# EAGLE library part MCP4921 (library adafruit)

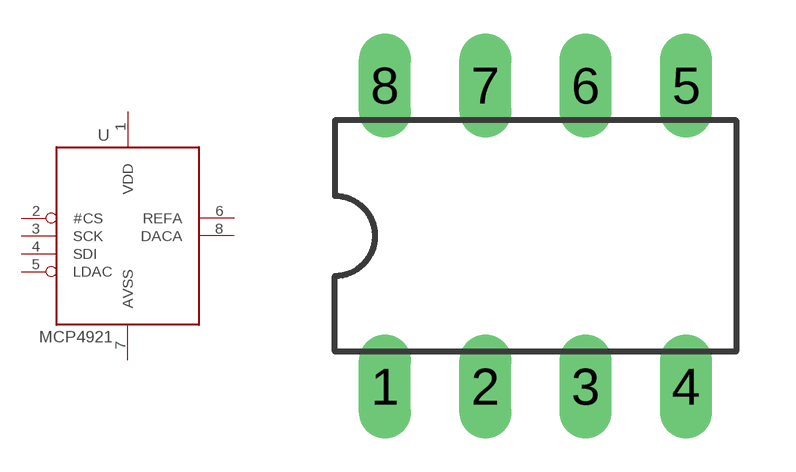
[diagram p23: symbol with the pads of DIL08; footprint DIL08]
Designator prefix -

## MCP4921  [DIL08]
1  VDD  sup
2  #CS  in
3  SCK  in
4  SDI  in
5  LDAC  in
6  REFA  in
7  AVSS  sup
8  DACA  out

## Footprint DIL08 (pad centres in mm)
Dual In Line Package
drill 0.813 long: 1 -3.81,-3.81; 2 -1.27,-3.81; 3 1.27,-3.81; 4 3.81,-3.81; 5 3.81,3.81; 6 1.27,3.81; 7 -1.27,3.81; 8 -3.81,3.81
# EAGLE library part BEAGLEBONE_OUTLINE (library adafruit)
Should match A3 pinout - but not completely tested

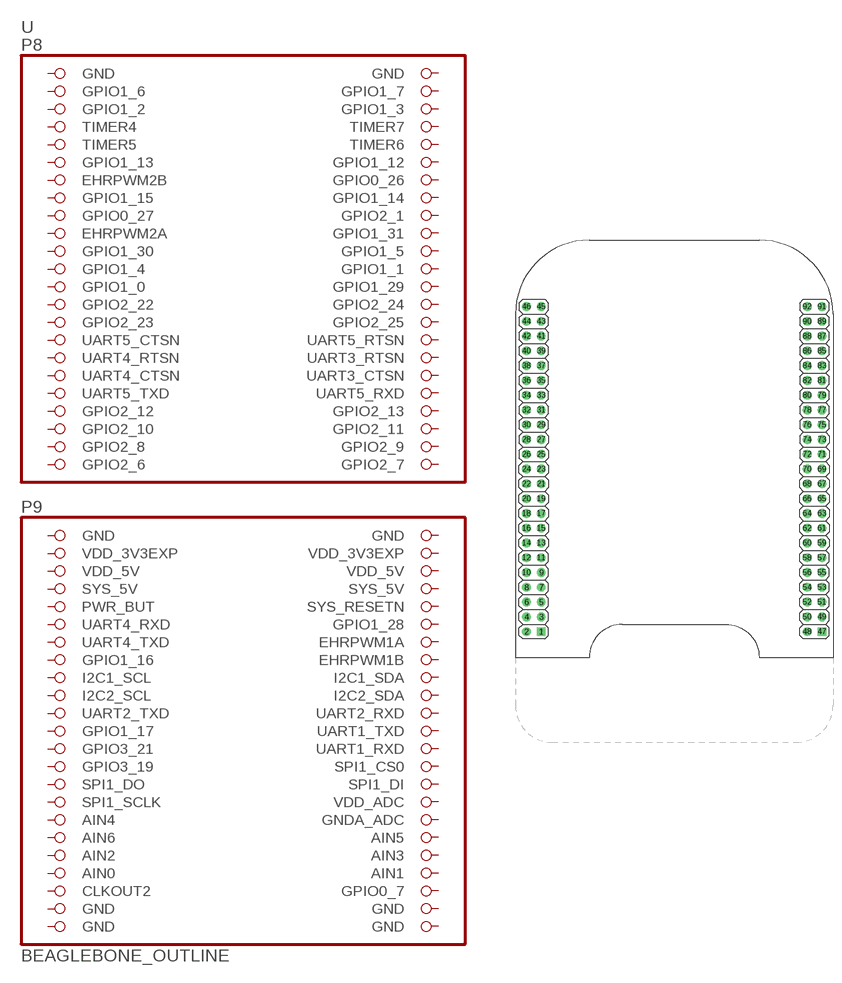
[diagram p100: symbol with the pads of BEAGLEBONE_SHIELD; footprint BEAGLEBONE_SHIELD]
Designator prefix -

## BEAGLEBONE_OUTLINE  [BEAGLEBONE_SHIELD]
1  GND  pwr
2  GND  pwr
3  GPIO1_6  pas
4  GPIO1_7  pas
5  GPIO1_2  pas
6  GPIO1_3  pas
7  TIMER4  pas
8  TIMER7  pas
9  TIMER5  pas
10  TIMER6  pas
11  GPIO1_13  pas
12  GPIO1_12  pas
13  EHRPWM2B  pas
14  GPIO0_26  pas
15  GPIO1_15  pas
16  GPIO1_14  pas
17  GPIO0_27  pas
18  GPIO2_1  pas
19  EHRPWM2A  pas
20  GPIO1_31  pas
21  GPIO1_30  pas
22  GPIO1_5  pas
23  GPIO1_4  pas
24  GPIO1_1  pas
25  GPIO1_0  pas
26  GPIO1_29  pas
27  GPIO2_22  pas
28  GPIO2_24  pas
29  GPIO2_23  pas
30  GPIO2_25  pas
31  UART5_CTSN  pas
32  UART5_RTSN  pas
33  UART4_RTSN  pas
34  UART3_RTSN  pas
35  UART4_CTSN  pas
36  UART3_CTSN  pas
37  UART5_TXD  pas
38  UART5_RXD  pas
39  GPIO2_12  pas
40  GPIO2_13  pas
41  GPIO2_10  pas
42  GPIO2_11  pas
43  GPIO2_8  pas
44  GPIO2_9  pas
45  GPIO2_6  pas
46  GPIO2_7  pas
47  GND  pwr
48  GND  pwr
49  VDD_3V3EXP  pwr
50  VDD_3V3EXP  pwr
51  VDD_5V  pwr
52  VDD_5V  pwr
53  SYS_5V  pwr
54  SYS_5V  pas
55  PWR_BUT  pas
56  SYS_RESETN  pas
57  UART4_RXD  pas
58  GPIO1_28  pas
59  UART4_TXD  pas
60  EHRPWM1A  pas
61  GPIO1_16  pas
62  EHRPWM1B  pas
63  I2C1_SCL  pas
64  I2C1_SDA  pas
65  I2C2_SCL  pas
66  I2C2_SDA  pas
67  UART2_TXD  pas
68  UART2_RXD  pas
69  GPIO1_17  pas
70  UART1_TXD  pas
71  GPIO3_21  pas
72  UART1_RXD  pas
73  GPIO3_19  pas
74  SPI1_CS0  pas
75  SPI1_DO  pas
76  SPI1_DI  pas
77  SPI1_SCLK  pas
78  VDD_ADC  pas
79  AIN4  pas
80  GNDA_ADC  pas
81  AIN6  pas
82  AIN5  pas
83  AIN2  pas
84  AIN3  pas
85  AIN0  pwr
86  AIN1  pas
87  CLKOUT2  in
88  GPIO0_7  pas
89  GND  pwr
90  GND  pwr
91  GND  pwr
92  GND  pwr

## Footprint BEAGLEBONE_SHIELD (pad centres in mm)
drill 1 square: 1 4.445,19.05; 47 52.705,19.05
drill 1: 2 1.905,19.05; 3 4.445,21.59; 4 1.905,21.59; 5 4.445,24.13; 6 1.905,24.13; 7 4.445,26.67; 8 1.905,26.67; 9 4.445,29.21; 10 1.905,29.21; 11 4.445,31.75; 12 1.905,31.75; 13 4.445,34.29; 14 1.905,34.29; 15 4.445,36.83; 16 1.905,36.83; 17 4.445,39.37; 18 1.905,39.37; 19 4.445,41.91; 20 1.905,41.91; 21 4.445,44.45; 22 1.905,44.45; 23 4.445,46.99; 24 1.905,46.99; 25 4.445,49.53; 26 1.905,49.53; 27 4.445,52.07; 28 1.905,52.07; 29 4.445,54.61; 30 1.905,54.61; 31 4.445,57.15; 32 1.905,57.15; 33 4.445,59.69; 34 1.905,59.69; 35 4.445,62.23; 36 1.905,62.23; 37 4.445,64.77; 38 1.905,64.77; 39 4.445,67.31; 40 1.905,67.31; 41 4.445,69.85; 42 1.905,69.85; 43 4.445,72.39; 44 1.905,72.39; 45 4.445,74.93; 46 1.905,74.93; 48 50.165,19.05; 49 52.705,21.59; 50 50.165,21.59; 51 52.705,24.13; 52 50.165,24.13; 53 52.705,26.67; 54 50.165,26.67; 55 52.705,29.21; 56 50.165,29.21; 57 52.705,31.75; 58 50.165,31.75; 59 52.705,34.29; 60 50.165,34.29; 61 52.705,36.83; 62 50.165,36.83; 63 52.705,39.37; 64 50.165,39.37; 65 52.705,41.91; 66 50.165,41.91; 67 52.705,44.45; 68 50.165,44.45; 69 52.705,46.99; 70 50.165,46.99; 71 52.705,49.53; 72 50.165,49.53; 73 52.705,52.07; 74 50.165,52.07; 75 52.705,54.61; 76 50.165,54.61; 77 52.705,57.15; 78 50.165,57.15; 79 52.705,59.69; 80 50.165,59.69; 81 52.705,62.23; 82 50.165,62.23; 83 52.705,64.77; 84 50.165,64.77; 85 52.705,67.31; 86 50.165,67.31; 87 52.705,69.85; 88 50.165,69.85; 89 52.705,72.39; 90 50.165,72.39; 91 52.705,74.93; 92 50.165,74.93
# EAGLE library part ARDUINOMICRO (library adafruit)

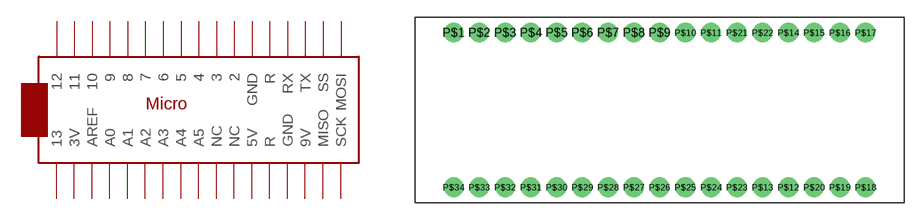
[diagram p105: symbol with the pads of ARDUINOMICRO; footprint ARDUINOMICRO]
Designator prefix -

## ARDUINOMICRO  [ARDUINOMICRO]
P$1  12
P$2  11
P$3  10
P$4  9
P$5  8
P$6  7
P$7  6
P$8  5
P$9  4
P$10  3
P$11  2
P$12  GND
P$13  R
P$14  RX
P$15  TX
P$16  SS
P$17  MOSI
P$18  SCK
P$19  MISO
P$20  9V
P$21  GND
P$22  R
P$23  5V
P$24  NC
P$25  NC
P$26  A5
P$27  A4
P$28  A3
P$29  A2
P$30  A1
P$31  A0
P$32  AREF
P$33  3V
P$34  13

## Footprint ARDUINOMICRO (pad centres in mm)
drill 1.1 pad 1.93: P$1 -20.32,7.62; P$2 -17.78,7.62; P$3 -15.24,7.62; P$4 -12.7,7.62; P$5 -10.16,7.62; P$6 -7.62,7.62; P$7 -5.08,7.62; P$8 -2.54,7.62; P$9 0,7.62; P$10 2.54,7.62; P$11 5.08,7.62; P$12 12.7,-7.62; P$13 10.16,-7.62; P$14 12.7,7.62; P$15 15.24,7.62; P$16 17.78,7.62; P$17 20.32,7.62; P$18 20.32,-7.62; P$19 17.78,-7.62; P$20 15.24,-7.62; P$21 7.62,7.62; P$22 10.16,7.62; P$23 7.62,-7.62; P$24 5.08,-7.62; P$25 2.54,-7.62; P$26 0,-7.62; P$27 -2.54,-7.62; P$28 -5.08,-7.62; P$29 -7.62,-7.62; P$30 -10.16,-7.62; P$31 -12.7,-7.62; P$32 -15.24,-7.62; P$33 -17.78,-7.62; P$34 -20.32,-7.62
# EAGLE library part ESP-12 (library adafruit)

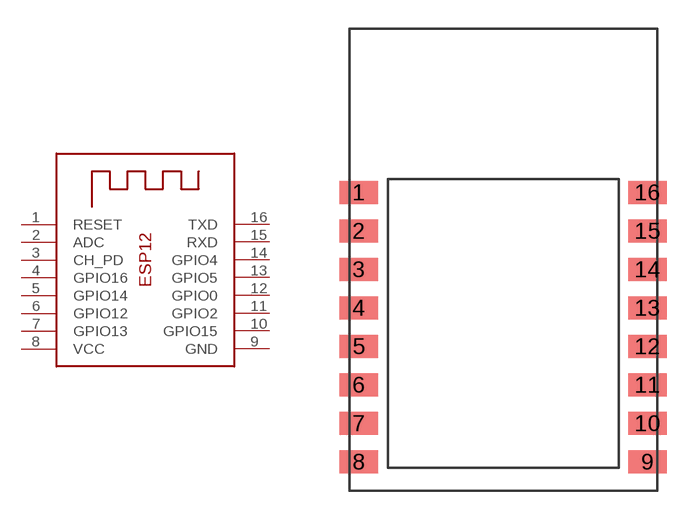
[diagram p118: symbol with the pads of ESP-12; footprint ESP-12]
Designator prefix X

## ESP-12  [ESP-12]
1  RESET  in
2  ADC  pas
3  CH_PD  in
4  GPIO16
5  GPIO14
6  GPIO12
7  GPIO13
8  VCC  pwr
9  GND  pwr
10  GPIO15
11  GPIO2
12  GPIO0
13  GPIO5
14  GPIO4
15  RXD  in
16  TXD  out

## Footprint ESP-12 (pad centres in mm)
smd 2 x 1.2: 1 -7.5,4.5; 2 -7.5,2.5; 3 -7.5,0.5; 4 -7.5,-1.5; 5 -7.5,-3.5; 6 -7.5,-5.5; 7 -7.5,-7.5; 8 -7.5,-9.5; 9 7.5,-9.5; 10 7.5,-7.5; 11 7.5,-5.5; 12 7.5,-3.5; 13 7.5,-1.5; 14 7.5,0.5; 15 7.5,2.5; 16 7.5,4.5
